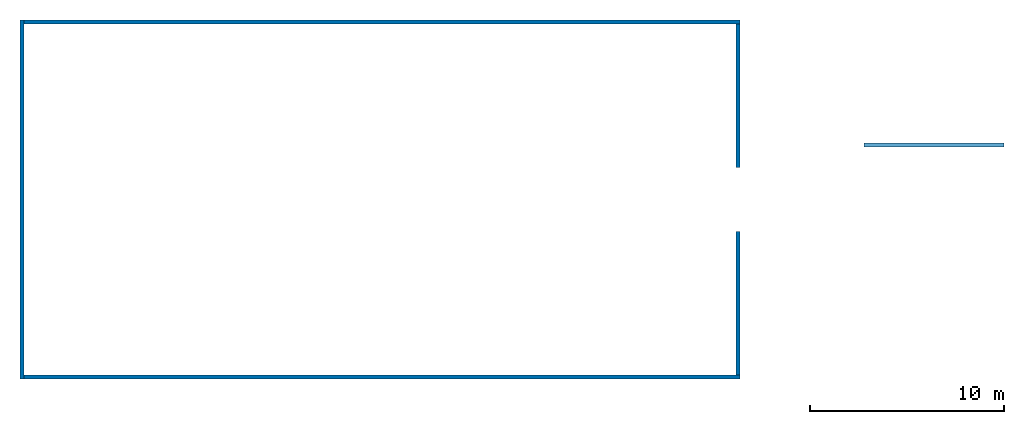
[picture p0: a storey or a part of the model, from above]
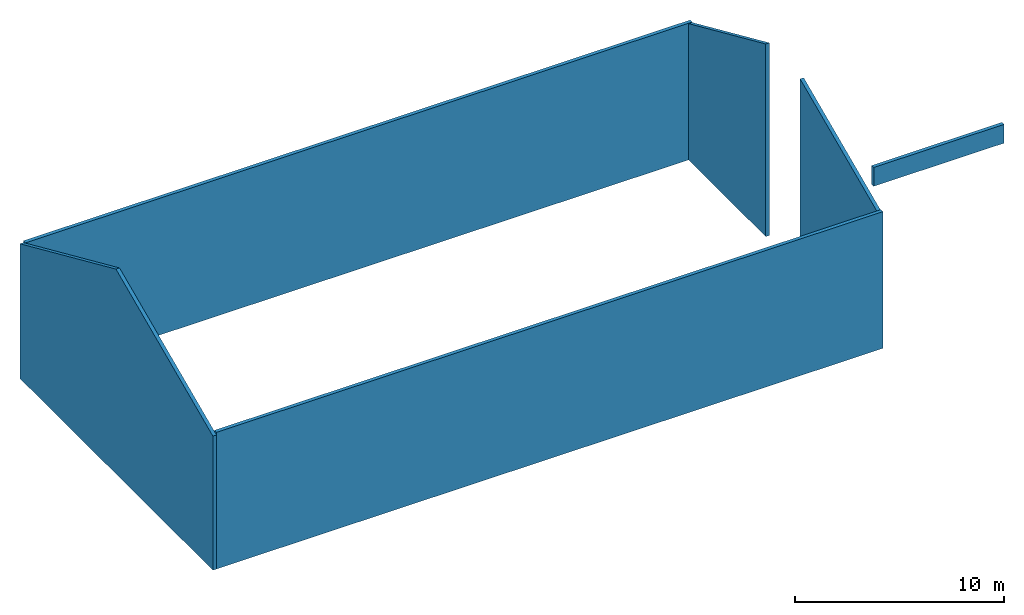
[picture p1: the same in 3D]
Properties of the parts of a building model (IFC2X3)

# File
Description: ViewDefinition [CoordinationView_V2.0]
File name: プロジェクト番号
Time: 2022-06-30T23:15:34+09:00
Written by: ODA SDAI 22.12
Made in: 23.0.1.318 - Exporter 23.0.1.318 - 代替 UI 23.0.1.318

# IfcProject, プロジェクト番号
LongName: プロジェクト名; Phase: プロジェクト ステータス

# IfcSite, Default
RefLatitude: 35, 41, 59, 999999; RefLongitude: 139, 45, 59, 999999; RefElevation: 0 mm

# IfcBuilding
Pset_BuildingCommon - NumberOfStoreys: 5

# IfcBuildingStorey: レベル:レベル記号 (5)
Name | LongName | Elevation (mm)
GL | GL | 0
1FL | 1FL | 1100
外部軒高さ | 外部軒高さ | 6000
外部最高高さ | 外部最高高さ | 7000
最高高さ | 最高高さ | 12150

# IfcBeam: HE-B:HEB200 (2)
In: 外部軒高さ
Type - Pset_BeamCommon - LoadBearing: yes; IsExternal: no
Material: 構造用鋼 - S235
Pset_BeamCommon - Reference: HEB200; Span: 14350 mm; Slope: 0 deg
Pset_QuantityTakeOff - Reference: HEB200; sets with these values: 2
Name (HE-B:HEB200:...)
304654
304708

# IfcColumn: 正方型鋼管-柱:HSS250x250x12 (4)
In: 1FL
Type - PredefinedType: COLUMN; Material: メタル - SN400
Type - Pset_ColumnCommon - LoadBearing: yes; IsExternal: no
Pset_ColumnCommon - Reference: HSS250x250x12
Pset_QuantityTakeOff - Reference: HSS250x250x12; sets with these values: 2
Name (正方型鋼管-柱:HSS250x250x12:...)
303011
303227
303316
303401

# IfcRoof: 標準屋根:スレート-150mm (2)
Material: 屋根、スレート 30 mm, 既定の屋根 120 mm
Pset_QuantityTakeOff - Reference: スレート-150mm
Pset_RoofCommon - IsExternal: yes; Reference: スレート-150mm
Name (標準屋根:スレート-150mm:...) | In | ProjectedArea (m2) | TotalArea (m2)
313025 | 外部最高高さ | 213.248 | 228.42
313620 | 最高高さ | 788.78 | 863.427

# IfcSlab: べた基礎:基礎スラブ (2)
In: 1FL
Type - PredefinedType: BASESLAB; Material: <Unnamed> 1100 mm
Type - Pset_SlabCommon - IsExternal: no
Pset_QuantityTakeOff - Reference: 基礎スラブ; sets with these values: 2
Pset_SlabCommon - LoadBearing: yes; Reference: 基礎スラブ; PitchAngle: 0 deg
Name (べた基礎:基礎スラブ:...)
306903
307997

# IfcSlab: 標準屋根:スレート-150mm (4)
Type - PredefinedType: ROOF
Type - Pset_SlabCommon - IsExternal: yes; ThermalTransmittance: 62.7667 kg/K/s3
Material: 屋根、スレート 30 mm, 既定の屋根 120 mm
Pset_QuantityTakeOff - Reference: スレート-150mm; sets with these values: 2
Pset_SlabCommon - Reference: スレート-150mm
Name (標準屋根:スレート-150mm:...) | In | PitchAngle (deg)
2 x 313025 | 外部最高高さ | 21
2 x 313620 | 最高高さ | 24

# IfcWallStandardCase: 標準壁:標準-200mm (7)
Type - PredefinedType: STANDARD; Material: 既定の壁 200 mm
Type - Pset_WallCommon - IsExternal: yes
Pset_QuantityTakeOff - Reference: 標準-200mm; sets with these values: 2
Pset_WallCommon - Reference: 標準-200mm; LoadBearing: yes
Name (標準壁:標準-200mm:...) | In | ExtendToStructure
301931 | GL | yes
302048 | GL | no
302104 | GL | yes
302207 | GL | no
307882 | GL | no
314625 | GL | yes
314910 | 1FL | yes
